# Generated by FakeRAM 2.0
VERSION 5.7 ;
BUSBITCHARS "[]" ;
PROPERTYDEFINITIONS
  MACRO width INTEGER ;
  MACRO depth INTEGER ;
  MACRO banks INTEGER ;
END PROPERTYDEFINITIONS
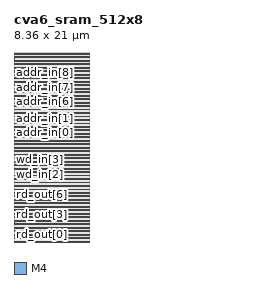
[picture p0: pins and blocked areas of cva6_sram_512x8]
MACRO cva6_sram_512x8
  PROPERTY width 8 ;
  PROPERTY depth 512 ;
  PROPERTY banks 1 ;
  FOREIGN cva6_sram_512x8 0 0 ;
  SYMMETRY X Y R90 ;
  SIZE 8.3600 BY 21.0000 ;
  CLASS BLOCK ;
  PIN rd_out[0]
    DIRECTION OUTPUT ;
    USE SIGNAL ;
    PORT
      LAYER M4 ;
      RECT 0.00000 0.04800 0.02400 0.07200 ;
    END
  END rd_out[0]
  PIN rd_out[1]
    DIRECTION OUTPUT ;
    USE SIGNAL ;
    PORT
      LAYER M4 ;
      RECT 0.00000 0.76800 0.02400 0.79200 ;
    END
  END rd_out[1]
  PIN rd_out[2]
    DIRECTION OUTPUT ;
    USE SIGNAL ;
    PORT
      LAYER M4 ;
      RECT 0.00000 1.48800 0.02400 1.51200 ;
    END
  END rd_out[2]
  PIN rd_out[3]
    DIRECTION OUTPUT ;
    USE SIGNAL ;
    PORT
      LAYER M4 ;
      RECT 0.00000 2.20800 0.02400 2.23200 ;
    END
  END rd_out[3]
  PIN rd_out[4]
    DIRECTION OUTPUT ;
    USE SIGNAL ;
    PORT
      LAYER M4 ;
      RECT 0.00000 2.92800 0.02400 2.95200 ;
    END
  END rd_out[4]
  PIN rd_out[5]
    DIRECTION OUTPUT ;
    USE SIGNAL ;
    PORT
      LAYER M4 ;
      RECT 0.00000 3.64800 0.02400 3.67200 ;
    END
  END rd_out[5]
  PIN rd_out[6]
    DIRECTION OUTPUT ;
    USE SIGNAL ;
    PORT
      LAYER M4 ;
      RECT 0.00000 4.36800 0.02400 4.39200 ;
    END
  END rd_out[6]
  PIN rd_out[7]
    DIRECTION OUTPUT ;
    USE SIGNAL ;
    PORT
      LAYER M4 ;
      RECT 0.00000 5.08800 0.02400 5.11200 ;
    END
  END rd_out[7]
  PIN wd_in[0]
    DIRECTION INPUT ;
    USE SIGNAL ;
    PORT
      LAYER M4 ;
      RECT 0.00000 6.04800 0.02400 6.07200 ;
    END
  END wd_in[0]
  PIN wd_in[1]
    DIRECTION INPUT ;
    USE SIGNAL ;
    PORT
      LAYER M4 ;
      RECT 0.00000 6.76800 0.02400 6.79200 ;
    END
  END wd_in[1]
  PIN wd_in[2]
    DIRECTION INPUT ;
    USE SIGNAL ;
    PORT
      LAYER M4 ;
      RECT 0.00000 7.48800 0.02400 7.51200 ;
    END
  END wd_in[2]
  PIN wd_in[3]
    DIRECTION INPUT ;
    USE SIGNAL ;
    PORT
      LAYER M4 ;
      RECT 0.00000 8.20800 0.02400 8.23200 ;
    END
  END wd_in[3]
  PIN wd_in[4]
    DIRECTION INPUT ;
    USE SIGNAL ;
    PORT
      LAYER M4 ;
      RECT 0.00000 8.92800 0.02400 8.95200 ;
    END
  END wd_in[4]
  PIN wd_in[5]
    DIRECTION INPUT ;
    USE SIGNAL ;
    PORT
      LAYER M4 ;
      RECT 0.00000 9.64800 0.02400 9.67200 ;
    END
  END wd_in[5]
  PIN wd_in[6]
    DIRECTION INPUT ;
    USE SIGNAL ;
    PORT
      LAYER M4 ;
      RECT 0.00000 10.36800 0.02400 10.39200 ;
    END
  END wd_in[6]
  PIN wd_in[7]
    DIRECTION INPUT ;
    USE SIGNAL ;
    PORT
      LAYER M4 ;
      RECT 0.00000 11.08800 0.02400 11.11200 ;
    END
  END wd_in[7]
  PIN addr_in[0]
    DIRECTION INPUT ;
    USE SIGNAL ;
    PORT
      LAYER M4 ;
      RECT 0.00000 12.04800 0.02400 12.07200 ;
    END
  END addr_in[0]
  PIN addr_in[1]
    DIRECTION INPUT ;
    USE SIGNAL ;
    PORT
      LAYER M4 ;
      RECT 0.00000 12.76800 0.02400 12.79200 ;
    END
  END addr_in[1]
  PIN addr_in[2]
    DIRECTION INPUT ;
    USE SIGNAL ;
    PORT
      LAYER M4 ;
      RECT 0.00000 13.48800 0.02400 13.51200 ;
    END
  END addr_in[2]
  PIN addr_in[3]
    DIRECTION INPUT ;
    USE SIGNAL ;
    PORT
      LAYER M4 ;
      RECT 0.00000 14.20800 0.02400 14.23200 ;
    END
  END addr_in[3]
  PIN addr_in[4]
    DIRECTION INPUT ;
    USE SIGNAL ;
    PORT
      LAYER M4 ;
      RECT 0.00000 14.92800 0.02400 14.95200 ;
    END
  END addr_in[4]
  PIN addr_in[5]
    DIRECTION INPUT ;
    USE SIGNAL ;
    PORT
      LAYER M4 ;
      RECT 0.00000 15.64800 0.02400 15.67200 ;
    END
  END addr_in[5]
  PIN addr_in[6]
    DIRECTION INPUT ;
    USE SIGNAL ;
    PORT
      LAYER M4 ;
      RECT 0.00000 16.36800 0.02400 16.39200 ;
    END
  END addr_in[6]
  PIN addr_in[7]
    DIRECTION INPUT ;
    USE SIGNAL ;
    PORT
      LAYER M4 ;
      RECT 0.00000 17.08800 0.02400 17.11200 ;
    END
  END addr_in[7]
  PIN addr_in[8]
    DIRECTION INPUT ;
    USE SIGNAL ;
    PORT
      LAYER M4 ;
      RECT 0.00000 17.80800 0.02400 17.83200 ;
    END
  END addr_in[8]
  PIN we_in
    DIRECTION INPUT ;
    USE SIGNAL ;
    PORT
      LAYER M4 ;
      RECT 0.00000 18.76800 0.02400 18.79200 ;
    END
  END we_in
  PIN clk
    DIRECTION INPUT ;
    USE SIGNAL ;
    PORT
      LAYER M4 ;
      RECT 0.00000 19.48800 0.02400 19.51200 ;
    END
  END clk
  PIN ce_in
    DIRECTION INPUT ;
    USE SIGNAL ;
    PORT
      LAYER M4 ;
      RECT 0.00000 20.20800 0.02400 20.23200 ;
    END
  END ce_in
  PIN VDD
    DIRECTION INOUT ;
    USE POWER ;
    PORT
      LAYER M4 ;
      RECT 0.04800 0.38400 8.31200 0.48000 ;
      RECT 0.04800 1.15200 8.31200 1.24800 ;
      RECT 0.04800 1.92000 8.31200 2.01600 ;
      RECT 0.04800 2.68800 8.31200 2.78400 ;
      RECT 0.04800 3.45600 8.31200 3.55200 ;
      RECT 0.04800 4.22400 8.31200 4.32000 ;
      RECT 0.04800 4.99200 8.31200 5.08800 ;
      RECT 0.04800 5.76000 8.31200 5.85600 ;
      RECT 0.04800 6.52800 8.31200 6.62400 ;
      RECT 0.04800 7.29600 8.31200 7.39200 ;
      RECT 0.04800 8.06400 8.31200 8.16000 ;
      RECT 0.04800 8.83200 8.31200 8.92800 ;
      RECT 0.04800 9.60000 8.31200 9.69600 ;
      RECT 0.04800 10.36800 8.31200 10.46400 ;
      RECT 0.04800 11.13600 8.31200 11.23200 ;
      RECT 0.04800 11.90400 8.31200 12.00000 ;
      RECT 0.04800 12.67200 8.31200 12.76800 ;
      RECT 0.04800 13.44000 8.31200 13.53600 ;
      RECT 0.04800 14.20800 8.31200 14.30400 ;
      RECT 0.04800 14.97600 8.31200 15.07200 ;
      RECT 0.04800 15.74400 8.31200 15.84000 ;
      RECT 0.04800 16.51200 8.31200 16.60800 ;
      RECT 0.04800 17.28000 8.31200 17.37600 ;
      RECT 0.04800 18.04800 8.31200 18.14400 ;
      RECT 0.04800 18.81600 8.31200 18.91200 ;
      RECT 0.04800 19.58400 8.31200 19.68000 ;
      RECT 0.04800 20.35200 8.31200 20.44800 ;
    END
  END VDD
  PIN VSS
    DIRECTION INOUT ;
    USE GROUND ;
    PORT
      LAYER M4 ;
      RECT 0.04800 0.00000 8.31200 0.09600 ;
      RECT 0.04800 0.76800 8.31200 0.86400 ;
      RECT 0.04800 1.53600 8.31200 1.63200 ;
      RECT 0.04800 2.30400 8.31200 2.40000 ;
      RECT 0.04800 3.07200 8.31200 3.16800 ;
      RECT 0.04800 3.84000 8.31200 3.93600 ;
      RECT 0.04800 4.60800 8.31200 4.70400 ;
      RECT 0.04800 5.37600 8.31200 5.47200 ;
      RECT 0.04800 6.14400 8.31200 6.24000 ;
      RECT 0.04800 6.91200 8.31200 7.00800 ;
      RECT 0.04800 7.68000 8.31200 7.77600 ;
      RECT 0.04800 8.44800 8.31200 8.54400 ;
      RECT 0.04800 9.21600 8.31200 9.31200 ;
      RECT 0.04800 9.98400 8.31200 10.08000 ;
      RECT 0.04800 10.75200 8.31200 10.84800 ;
      RECT 0.04800 11.52000 8.31200 11.61600 ;
      RECT 0.04800 12.28800 8.31200 12.38400 ;
      RECT 0.04800 13.05600 8.31200 13.15200 ;
      RECT 0.04800 13.82400 8.31200 13.92000 ;
      RECT 0.04800 14.59200 8.31200 14.68800 ;
      RECT 0.04800 15.36000 8.31200 15.45600 ;
      RECT 0.04800 16.12800 8.31200 16.22400 ;
      RECT 0.04800 16.89600 8.31200 16.99200 ;
      RECT 0.04800 17.66400 8.31200 17.76000 ;
      RECT 0.04800 18.43200 8.31200 18.52800 ;
      RECT 0.04800 19.20000 8.31200 19.29600 ;
      RECT 0.04800 19.96800 8.31200 20.06400 ;
      RECT 0.04800 20.73600 8.31200 20.83200 ;
    END
  END VSS
  OBS
    LAYER M1 ;
    RECT 0 0 8.36000 21.00000 ;
    LAYER M2 ;
    RECT 0 0 8.36000 21.00000 ;
    LAYER M3 ;
    RECT 0 0 8.36000 21.00000 ;
    LAYER M4 ;
    RECT 0 0 8.36000 21.00000 ;
  END
END cva6_sram_512x8

END LIBRARY
